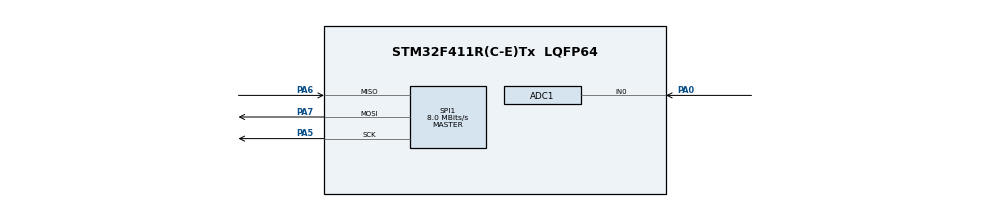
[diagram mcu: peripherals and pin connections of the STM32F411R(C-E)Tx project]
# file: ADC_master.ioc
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ADC1.Channel-0\#ChannelRegularConversion=ADC_CHANNEL_0
ADC1.NbrOfConversionFlag=1
ADC1.Rank-0\#ChannelRegularConversion=1
ADC1.SamplingTime-0\#ChannelRegularConversion=ADC_SAMPLETIME_3CYCLES
ADC1.master=1
Mcu.Family=STM32F4
Mcu.Name=STM32F411R(C-E)Tx
Mcu.Package=LQFP64
NVIC.PriorityGroup=NVIC_PRIORITYGROUP_4
PA0-WKUP.Signal=ADCx_IN0
PA5.Mode=Full_Duplex_Master
PA5.Signal=SPI1_SCK
PA6.Mode=Full_Duplex_Master
PA6.Signal=SPI1_MISO
PA7.Mode=Full_Duplex_Master
PA7.Signal=SPI1_MOSI
ProjectManager.HeapSize=0x200
ProjectManager.StackSize=0x400
ProjectManager.TargetToolchain=MDK-ARM V5.32
RCC.AHBFreq_Value=16000000
RCC.APB1Freq_Value=16000000
RCC.APB2Freq_Value=16000000
RCC.CortexFreq_Value=16000000
RCC.HSE_VALUE=25000000
RCC.HSI_VALUE=16000000
RCC.LSE_VALUE=32768
RCC.SYSCLKFreq_VALUE=16000000
RCC.VCOOutputFreq_Value=192000000
SH.ADCx_IN0.0=ADC1_IN0,IN0
SPI1.CalculateBaudRate=8.0 MBits/s
SPI1.Direction=SPI_DIRECTION_2LINES
SPI1.Mode=SPI_MODE_MASTER
SPI1.VirtualType=VM_MASTER
board=custom

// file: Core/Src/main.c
/* USER CODE BEGIN Header */
/**
  ******************************************************************************
  * @file           : main.c
  * @brief          : Main program body
  ******************************************************************************
  * @attention
  *
  * Copyright (c) 2025 STMicroelectronics.
  * All rights reserved.
  *
  * This software is licensed under terms that can be found in the LICENSE file
  * in the root directory of this software component.
  * If no LICENSE file comes with this software, it is provided AS-IS.
  *
  ******************************************************************************
  */
/* USER CODE END Header */
#include "main.h"

ADC_HandleTypeDef hadc1;

SPI_HandleTypeDef hspi1;

/* USER CODE BEGIN PV */
uint16_t adc_value;
uint8_t tx_buffer[2]; // 2 bytes because adc_value is 16 bits
/* USER CODE END PV */

void SystemClock_Config(void);
static void MX_GPIO_Init(void);
static void MX_ADC1_Init(void);
static void MX_SPI1_Init(void);

int main(void)
{

  /* MCU Configuration--------------------------------------------------------*/

  /* Reset of all peripherals, Initializes the Flash interface and the Systick. */
  HAL_Init();

  /* Configure the system clock */
  SystemClock_Config();

  /* Initialize all configured peripherals */
  MX_GPIO_Init();
  MX_ADC1_Init();
  MX_SPI1_Init();

  /* Infinite loop */
  /* USER CODE BEGIN WHILE */
while (1)
  {
    // Start ADC Conversion
    HAL_ADC_Start(&hadc1);
    if (HAL_ADC_PollForConversion(&hadc1, 10) == HAL_OK)
    {
      adc_value = HAL_ADC_GetValue(&hadc1);
    }
    HAL_ADC_Stop(&hadc1);

    // Prepare tx buffer (split 16-bit into 2 bytes)
    tx_buffer[1] = adc_value >> 8;      // High byte
    tx_buffer[0] = adc_value & 0xFF;    // Low byte

    // Pull NSS Low
    HAL_GPIO_WritePin(GPIOA, GPIO_PIN_4, GPIO_PIN_RESET);

    // Transmit ADC value
    HAL_SPI_Transmit(&hspi1, tx_buffer, 2, 100);

    // Pull NSS High
    HAL_GPIO_WritePin(GPIOA, GPIO_PIN_4, GPIO_PIN_SET);

    HAL_Delay(500); // Wait half a second
  }
  /* USER CODE END 3 */
}

void SystemClock_Config(void)
{
  RCC_OscInitTypeDef RCC_OscInitStruct = {0};
  RCC_ClkInitTypeDef RCC_ClkInitStruct = {0};

  // Configure Voltage regulator
  __HAL_RCC_PWR_CLK_ENABLE();
  __HAL_PWR_VOLTAGESCALING_CONFIG(PWR_REGULATOR_VOLTAGE_SCALE1);

  // Configure Oscillator
  RCC_OscInitStruct.OscillatorType = RCC_OSCILLATORTYPE_HSI;
  RCC_OscInitStruct.HSIState = RCC_HSI_ON;
  RCC_OscInitStruct.HSICalibrationValue = RCC_HSICALIBRATION_DEFAULT;
  RCC_OscInitStruct.PLL.PLLState = RCC_PLL_ON;
  RCC_OscInitStruct.PLL.PLLSource = RCC_PLLSOURCE_HSI;
  RCC_OscInitStruct.PLL.PLLM = 16;
  RCC_OscInitStruct.PLL.PLLN = 336;
  RCC_OscInitStruct.PLL.PLLP = RCC_PLLP_DIV4; // SYSCLK = 84MHz
  RCC_OscInitStruct.PLL.PLLQ = 7;
  if (HAL_RCC_OscConfig(&RCC_OscInitStruct) != HAL_OK)
    Error_Handler();

  // Configure Clocks
  RCC_ClkInitStruct.ClockType = RCC_CLOCKTYPE_HCLK|RCC_CLOCKTYPE_SYSCLK
                                |RCC_CLOCKTYPE_PCLK1|RCC_CLOCKTYPE_PCLK2;
  RCC_ClkInitStruct.SYSCLKSource = RCC_SYSCLKSOURCE_PLLCLK;
  RCC_ClkInitStruct.AHBCLKDivider = RCC_SYSCLK_DIV1;
  RCC_ClkInitStruct.APB1CLKDivider = RCC_HCLK_DIV2;
  RCC_ClkInitStruct.APB2CLKDivider = RCC_HCLK_DIV1;
  if (HAL_RCC_ClockConfig(&RCC_ClkInitStruct, FLASH_LATENCY_2) != HAL_OK)
    Error_Handler();
}

static void MX_ADC1_Init(void)
{
  ADC_ChannelConfTypeDef sConfig = {0};

  __HAL_RCC_ADC1_CLK_ENABLE();

  hadc1.Instance = ADC1;
  hadc1.Init.ClockPrescaler = ADC_CLOCK_SYNC_PCLK_DIV4;
  hadc1.Init.Resolution = ADC_RESOLUTION_12B;
  hadc1.Init.ScanConvMode = DISABLE;
  hadc1.Init.ContinuousConvMode = DISABLE;
  hadc1.Init.DiscontinuousConvMode = DISABLE;
  hadc1.Init.ExternalTrigConvEdge = ADC_EXTERNALTRIGCONVEDGE_NONE;
  hadc1.Init.DataAlign = ADC_DATAALIGN_RIGHT;
  hadc1.Init.NbrOfConversion = 1;
  hadc1.Init.DMAContinuousRequests = DISABLE;
  hadc1.Init.EOCSelection = ADC_EOC_SINGLE_CONV;
  if (HAL_ADC_Init(&hadc1) != HAL_OK)
    Error_Handler();

  sConfig.Channel = ADC_CHANNEL_0;
  sConfig.Rank = 1;
  sConfig.SamplingTime = ADC_SAMPLETIME_480CYCLES;
  if (HAL_ADC_ConfigChannel(&hadc1, &sConfig) != HAL_OK)
    Error_Handler();
}

static void MX_SPI1_Init(void)
{
  __HAL_RCC_SPI1_CLK_ENABLE();

  hspi1.Instance = SPI1;
  hspi1.Init.Mode = SPI_MODE_MASTER;
  hspi1.Init.Direction = SPI_DIRECTION_2LINES;
  hspi1.Init.DataSize = SPI_DATASIZE_8BIT;
  hspi1.Init.CLKPolarity = SPI_POLARITY_LOW;
  hspi1.Init.CLKPhase = SPI_PHASE_1EDGE;
  hspi1.Init.NSS = SPI_NSS_SOFT;
  hspi1.Init.BaudRatePrescaler = SPI_BAUDRATEPRESCALER_64;
  hspi1.Init.FirstBit = SPI_FIRSTBIT_MSB;
  hspi1.Init.TIMode = SPI_TIMODE_DISABLE;
  hspi1.Init.CRCCalculation = SPI_CRCCALCULATION_DISABLE;
  hspi1.Init.CRCPolynomial = 10;
  if (HAL_SPI_Init(&hspi1) != HAL_OK)
    Error_Handler();
}
static void MX_GPIO_Init(void)
{
  GPIO_InitTypeDef GPIO_InitStruct = {0};

  __HAL_RCC_GPIOA_CLK_ENABLE();

  // Configure NSS (PA4) as Output
  GPIO_InitStruct.Pin = GPIO_PIN_4;
  GPIO_InitStruct.Mode = GPIO_MODE_OUTPUT_PP;
  GPIO_InitStruct.Pull = GPIO_NOPULL;
  GPIO_InitStruct.Speed = GPIO_SPEED_FREQ_VERY_HIGH;
  HAL_GPIO_Init(GPIOA, &GPIO_InitStruct);
}

void Error_Handler(void)
{
  __disable_irq();
  while (1)
  {
  }
}
